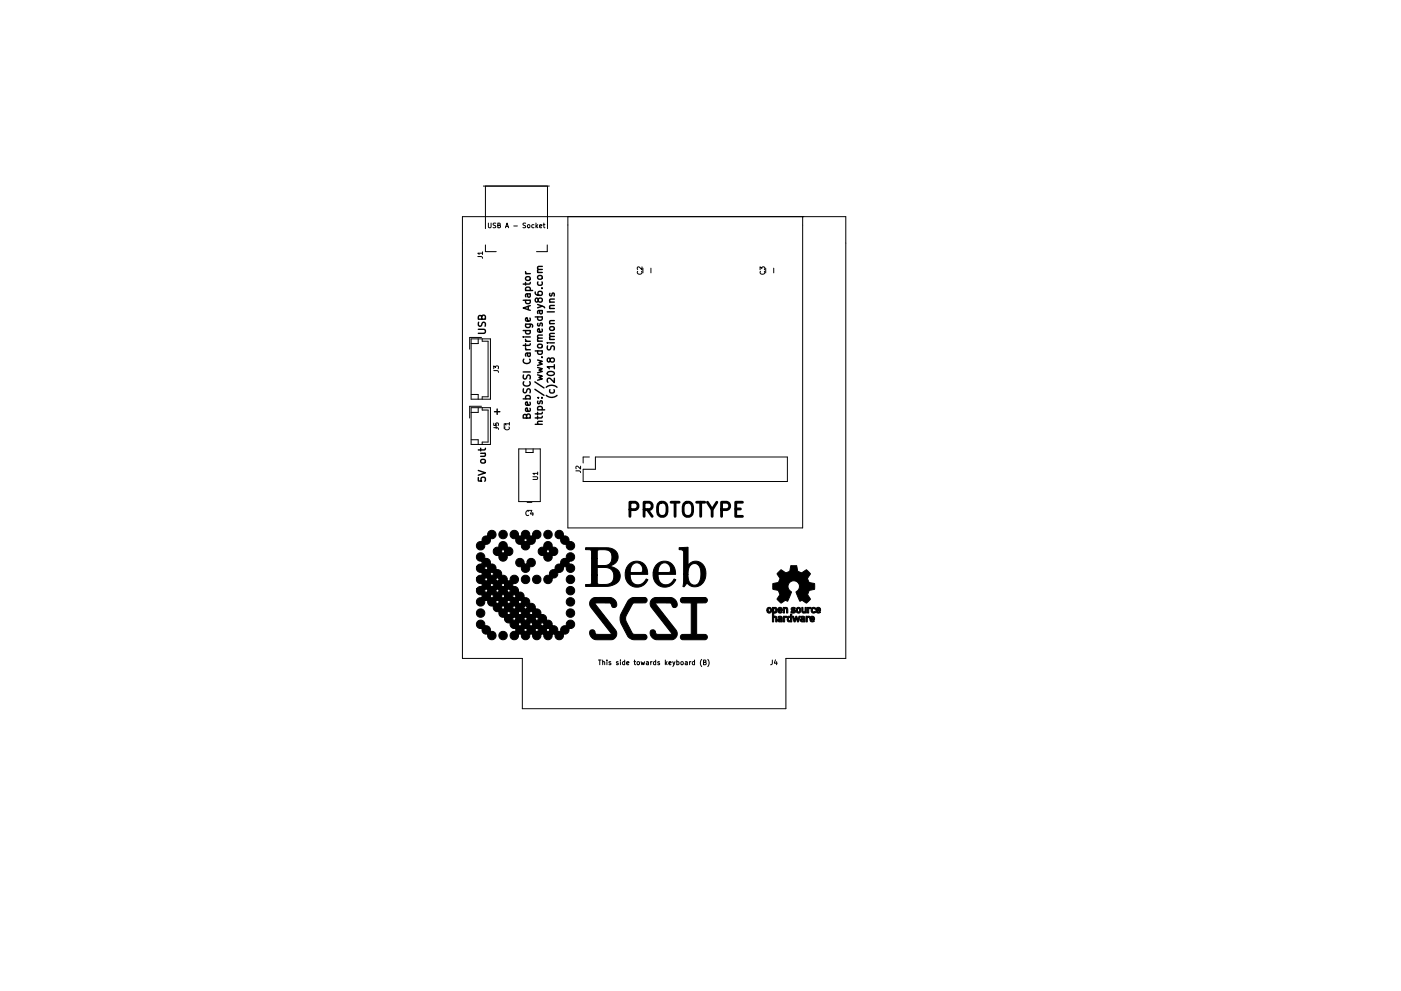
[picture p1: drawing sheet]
<svg xmlns="http://www.w3.org/2000/svg" width="297mm" height="210mm" viewBox="0 0 297 210" stroke-linecap="round" stroke-linejoin="round" font-family="sans-serif">
<g fill="none" stroke="#000" stroke-width=".3">
<path d="M111.4 57.6l.3 .5M111.4 59.9v.6M111.4 58.1h1M111.5 58.8l.6-.1 .3 .1v.4l-.3 .3h-.4l-.3-.3zM112.4 59.9l-.2 .4h-1.3M114 57.8h1M114.1 59.8l-.1 .4 .3 .3 .6-.1v-.6M114.1 58.5h.7l.2 .2-.1 .4-.2 .1h-.6l-.1-.2zM115 57.2h-.9l-.1 .4 .1 .2M115 56.5l-.9 .1-.1 .4 .2 .2M101.4 69.9h1.2l.3 .2v.3l-.3 .3h-1.2M101.5 68.4l-.1 .5 .3 .3 .4-.1 .2-.7h.5l.1 .2-.1 .6"/>
<path d="M102.1 67.2l.3-.3h.4l.1 .2v.6h-1.5l.2-.7 .2-.1 .3 .2v.6M110.9 71.5h.2M110.9 78.9h1.5M110.9 70.1h1.5M110.9 63.7h1.5M111 79.6l-.1 .5 .2 .2h.4l.3-.6 .3-.1 .3 .2v.6M111.1 76.2a.71 .71 0 0 0 .5 1 .71 .71 0 0 0 .8-.7l-.1-.3M111.4 73.8l.3 .4M111.4 72l.3 .4M111.4 68.8h1.2l.3 .3v.3M111.4 74.2h1M111.4 72.9v.6"/>
<path d="M111.4 72.4h1M111.4 71.5h1M111.4 61.6h1.5M111.5 70.1l-.1 .5 .3 .2 .7-.1v-.6M111.5 68.8l-.1 .4 .3 .3 .7-.2v-.5M111.5 63.7l-.1 .4 .3 .3 .7-.1v-.6M111.5 61.6l-.1-.4 .3-.3 .7 .2v.5M111.8 74.9l.1 .5 .2 .2 .3-.2v-.5M111.8 62.3l.1 .5 .2 .3 .3-.3v-.5M112 65v.7M112.4 67.5v.4l-.2 .2h-.7v-.6l.3-.1 .1 .7M112.4 74.9l-.9 .1v.6"/>
<path d="M112.4 72.9l-.2 .4h-1.3M112.4 64.8l-1.5 .5 1.5 .5M112.4 62.3l-.9 .1v.6M113.5 62v.4a1.01 1.01 0 0 0 1.5 0l-.2-.5-.5-.1-.2 .3v.4l.2 .2M113.5 74.5h1.5M113.5 67.2h1.5M114 79.5l1 .3-.7 .3 .7 .3-1 .3M114 78l1 .2-.7 .3 .7 .3-1 .3M114 76.4l1 .3-.7 .3 .7 .2-1 .3M114 64.6l1.3 .5 .2 .2M114 72.4h1M114.1 74.5l-.1 .4 .3 .3 .6-.2v-.5"/>
<path d="M114.1 68.6l-.1 .4 .2 .2 .2-.1 .1-.5h.4v.6M114.1 67.2l-.1 .5 .3 .3 .6-.2v-.6M114.1 73.1h.7l.2 .2-.1 .4-.2 .1-.6-.1-.1-.2zM114.1 63.5l.3-.3h.3l.3 .3-.2 .5-.4 .1-.2-.1-.2-.7-.5 .1v.4l.1 .2 .2 .1 .3-.3M114.3 65.9l.1 .5 .2 .2 .4-.2-.1-.5M114.8 75.8h.2M114.8 61.2h.2M114.9 69.8l.1 .4-.2 .3-.7-.1v-.6l.2-.1 .2 .8M115 71.7l-.9 .1-.1 .4 .1 .2M115 71.1l-.9 .1-.1 .3 .2 .2M115 65.9l-.9 .1v.5M115 65l-1 .3"/>
<path d="M116 72.7h.2M116 66.2h1.5M116.1 79a.89 .89 0 0 1 1.4 .3 .85 .85 0 0 1-1.5-.1zM116.1 73.4l-.1 .6 .2 .2h.4l.3-.7 .3-.1 .3 .3v.5M116.5 72.7h1M116.5 72h1M116.5 68.7h1M116.5 65.5h1M116.5 64.1h1M116.6 69.5l.6-.2 .3 .2v.3l-.3 .3h-.4l-.3-.3zM116.6 62.2l-.1 .4 .2 .2 .3-.1 .1-.5h.4v.6M116.7 76.2l.3-.2h.2l.3 .2v.5l-.5 .1-.3-.1-.2-.7-.4 .1-.1 .4 .2 .2 .2 .1 .3-.3"/>
<path d="M117.5 77.8h-1.5l.5 .4M117.5 71.4l-.9 .1-.1 .3 .2 .2M117.5 70.7l-.9 .1-.1 .4 .2 .2M117.5 68l-.9 .1-.1 .4 .2 .2M117.5 64.8l-.9 .1-.1 .3 .2 .3M117.5 63.5h-.9l-.1 .4 .2 .2M117.5 77.4v.8M101.4 99.8l1.5 .5-1.5 .5M101.9 96.2h1M101.9 95.1v.6M102 97.6l.6-.1 .2 .1 .1 .4-.3 .2h-.4l-.3-.2zM102.8 96.2l.1 .2-.1 .3-.9 .1"/>
<path d="M102.9 95.1l-.2 .4h-1.3M104.8 87.4h1.2M105.4 86.8v1.1M110.9 84.6h1.5M111 82.5l-.1 .6 .2 .2h.4l.3-.7 .3-.1 .3 .3v.5M111.1 81a.71 .71 0 0 0 .5 1 .71 .71 0 0 0 .8-.7l-.1-.3M111.5 84.6l-.1-.4 .3-.3 .7 .2v.5M111.6 88.2l.3-.4 .4 .1 .1 .2v.6h-1.5l.2-.7 .3-.1 .2 .2v.6M112.4 86.6v.5l-.2 .2-.7-.1v-.6h.3l.1 .7M112.4 85.3v.5l-.2 .2-.7-.1v-.6h.3l.1 .7M113.4 82.6l1.9 1.3M113.4 81l1.9 1.3"/>
<path d="M113.5 90h1.5M114 87.5v.5M114 88.3v.6M114 87h1.5M114.1 87l-.1-.5 .3-.3 .6 .2v.6M114.1 85.1l-.1 .4 .2 .2 .2-.1 .1-.5h.4v.6M114.1 84.4h.1M114.8 84.4h.2M115 89.4l-.9 .1-.1 .3 .1 .2M115 88.3l-.2 .4h-1.3M115 87.5l-.2 .3h-1.3M115.8 83.9a1.72 1.72 0 0 0 2.3 0"/>
<path d="M115.8 82.2a1.72 1.72 0 0 1 2.3 0M116.6 82.7l-.1 .4 .3 .3 .7-.2v-.5M117.5 80.2v1l-1-1-.5 .3 .2 .6M101.4 101.3v.7l.7 .1-.1-.2 .1-.5 .2-.2 .5 .1 .1 .2-.1 .6"/>
</g>
<g fill="none" stroke="#000" stroke-width=".21">
<path d="M102.5 39.5h14M102.9 39.5v9M116.1 39.5v9M98 46h81.3v93.7h-12.7v10.7h-55.9v-10.7h-12.7zM101.3 54.4l.9 .1 .1 .3M102.3 53.7h-1l.3 .3M102.3 53.4v.6M102.9 53.4h2.3M102.9 52v1.4M103.5 47.3v.8l.2 .2 .4-.2v-.8M105.1 47.4h-.5a.42 .42 0 0 0 .5 .5l-.1 .4h-.5M105.5 47.8h.5v-.4l-.5-.1v1h.4l.2-.3-.2-.2"/>
<path d="M107.2 48.3l.3-1 .3 1M107.3 48h.4M108.9 47.9h.8M111.5 47.4h-.6a.42 .42 0 0 0 .5 .5v.4h-.5M111.9 47.7h.3l.2 .1v.3l-.2 .2-.4-.2zM113.2 47.7h-.3l-.2 .1 .1 .5h.4M113.6 47.3v1M113.7 47.9l.3 .4M114 47.7l-.4 .3M114.4 48l.5-.1-.1-.2h-.3l-.1 .1 .1 .5h.3M115.2 47.7h.3M115.3 47.3v.9l.2 .1"/>
<path d="M116 52v1.4h-2.3M120.4 46v66h49.8v-66M135.2 57.6a.44 .44 0 0 0 .4 .6 .44 .44 0 0 0 .4-.6M136.1 56.6v.6l-.7-.6-.3 .2 .1 .4M136.3 56.9v1M138 56.9v1M161.1 57.2v-.6l.4 .3 .1-.2h.5v.5M161.2 57.6a.44 .44 0 0 0 .4 .6 .44 .44 0 0 0 .5-.6M162.3 56.9v1M164 56.9v1M99.9 71.9h4.1v12.8h-4.1zM101.4 71.9v1h-1.5"/>
<path d="M102.1 71.6h-2.5v2.5M102.2 71.9v.5h1.3v11.8h-1.3v.5M104.7 78.6l.8 .1 .2 .3M104.7 78.2v-.6l.4 .4 .1-.3h.4v.5M99.9 86.5h4.1v7.8h-4.1zM99.9 83.7h1.5v1M99.9 93.3h1.5v1M101.4 86.5v1h-1.5M102.1 86.2h-2.5v2.5M102.2 86.5v.5h1.3v6.8h-1.3v.5M104.7 90.7l.8 .1 .2 .3M104.7 89.8v.5h.5l-.1-.5h.5v.5"/>
<path d="M105.2 89.9v1M106.9 89.9v1M107.1 90.6a.44 .44 0 0 0 .4 .6 .44 .44 0 0 0 .4-.6M108 89.9h-1l.3 .3M108 89.6v.6M110 95.2h4.6v11.2h-4.6zM111.5 95.2v.8h1.5v-.8M122.1 99.9h.8l.2 .4M123.1 98.9v.6l-.7-.6-.3 .2 .1 .4M125 97h-1.4v1.2M126.2 97h40.7v5.2h-43.3v-2.6h2.6zM111.8 108.3h1"/>
<path d="M111.8 106.6h1M112.1 108.5a.44 .44 0 0 0-.6 .4 .44 .44 0 0 0 .6 .4M112.7 108.3l-.2 .8h.6M113 108.7v.7M113 101.1h.8l.2 .2-.2 .4h-.8M114 100.4h-1l.3 .3M114 100.1v.6M148.8 139.9a1.15 1.15 0 0 0 0 1.5M150.1 139.9a1.15 1.15 0 0 1 0 1.5M164.4 140l-.2 .7h.6M126.9 140h.5M127.2 140v1"/>
<path d="M127.8 140.5l.4-.1v.6M127.8 140v1M128.7 140v.1M128.7 140.4v.6M129.5 140.4l-.4 .1 .4 .2v.3h-.4M131.1 140.4l-.4 .1 .4 .2v.3h-.4M131.5 140v.1M131.5 140.4v.6M132.4 140.4h-.2l-.2 .2 .1 .4h.3M132.4 140v1M132.9 140.7l.5-.1-.1-.2h-.3l-.1 .1v.5h.4M134.4 140.4h.4"/>
<path d="M134.5 140v.9l.3 .1M135.1 140.5h.4v.5l-.4-.1zM135.9 140.4l.2 .6 .2-.4 .2 .4 .2-.6M137.1 140.4h.3l.1 .6M137.5 140.6l-.5 .2 .2 .2h.3M138 140.4v.6M138.3 140.4l-.3 .2M139 140.4h-.3l-.2 .2 .1 .4h.4M139 140v1M139.8 140.4l-.4 .1 .4 .2v.3h-.4M141.1 140v1M141.2 140.7l.2 .3"/>
<path d="M141.4 140.4l-.3 .3M141.8 140.7l.5-.1v-.2h-.3l-.2 .1 .1 .5h.4M142.6 140.4l.3 .6M143.1 140.4l-.5 1M143.5 140.4h.3l.2 .2-.1 .4h-.4M143.5 140v1M144.4 140.5h.4v.5l-.4-.1zM145.3 140.4h.4v.6M145.7 140.6l-.4 .2 .1 .2h.3M146.2 140.4v.6M146.5 140.4l-.3 .2M147.3 140.4h-.3l-.2 .2 .1 .4h.4"/>
<path d="M147.3 140v1M149.2 140.5h.4v-.4l-.4-.1v1h.3l.2-.3-.2-.2M163.8 140l-.1 .9-.3 .1M164.7 140.4v.6"/>
</g>
<g fill="none" stroke="#000" stroke-width=".6">
<path d="M133.6 108.1h1.1a.81 .81 0 0 0 .6-.8 .81 .81 0 0 0-.6-.7h-1.1v3M136.6 108.1h1.1a.81 .81 0 0 0 .6-.8 .81 .81 0 0 0-.6-.7h-1.1v3M137.3 108.1l1 1.5M139.6 107a1.01 1.01 0 0 1 1.1-.4 1.01 1.01 0 0 1 .7 1v1a1 1 0 0 1-1 1 1 1 0 0 1-1-1zM142.3 106.6h1.7M143.1 106.6v3M145 107a1.01 1.01 0 0 1 1.1-.4 1.01 1.01 0 0 1 .7 1v1a1 1 0 0 1-1 1 1 1 0 0 1-1-1zM147.7 106.6h1.7M148.6 106.6v3M150 106.6l1 1.5 1-1.5M151 108.1v1.5M153 108.1h1.1a.81 .81 0 0 0 .6-.8 .81 .81 0 0 0-.6-.7h-1.1v3"/>
<path d="M156 108h1M157.4 106.6h-1.4v3h1.4"/>
</g>
<g fill="#000" stroke="#000" stroke-width=".21">
<path d="M101.3 117.5l.5-.2a.89 .89 0 0 1 .9 1.2h.3a.9 .9 0 0 1 .9 1.2h.3a.9 .9 0 0 1 .9 1.2h.3a.9 .9 0 0 1 .9 1.2l.2-.1a.9 .9 0 0 1 1 1.3h.7v-.3a.9 .9 0 0 1 .9-1 .9 .9 0 0 1 .8 1.2 .9 .9 0 0 1-1.2 .6v.7l.2-.1a.9 .9 0 0 1 1 1.3l.2-.1a.9 .9 0 0 1 .9 1.3l.3-.1a.9 .9 0 0 1 .9 1.3l.3-.1a.9 .9 0 0 1 .9 1.3l.3-.1a.9 .9 0 0 1 .9 1.3l.3-.1a.9 .9 0 0 1 .9 1.2h.3a.9 .9 0 0 1 .9 1.2h.3a.9 .9 0 0 1 .9 1.2h.7v-.2a.9 .9 0 0 1 1.2-1v-.2a.9 .9 0 0 1 .9-1 .9 .9 0 0 1 .8 1.1 .9 .9 0 0 1-1.2 .6v.2a.9 .9 0 0 1-1.2 1l.1 .2a.9 .9 0 0 1-1.1 1 .9 .9 0 0 1-.7-1.2h-.7l.1 .2a.9 .9 0 0 1-1.1 1 .9 .9 0 0 1-.6-1.2h-.8l.1 .2a.9 .9 0 0 1-1 1 .9 .9 0 0 1-.7-1.2h-.8l.1 .2a.9 .9 0 0 1-1 1 .9 .9 0 0 1-.7-1.2h-.7v.2a.9 .9 0 0 1-.9 1 .9 .9 0 0 1-.8-1.1 .9 .9 0 0 1 1.2-.6v-.7h1.6l.1 .4a.19 .19 0 0 0 0 .3 .19 .19 0 0 0 .3 0h.4v-.7h1.6l.1 .4a.19 .19 0 0 0 0 .3 .19 .19 0 0 0 .3 0h.4v-.7h1.6l.1 .4a.19 .19 0 0 0 0 .3 .19 .19 0 0 0 .3 0h.4v-.7h-7.4a.9 .9 0 0 1-1-1.2h1.7v.4a.19 .19 0 0 0 0 .3 .19 .19 0 0 0 .3 0h.4v-.7h1.6l.1 .4a.19 .19 0 0 0 0 .3 .19 .19 0 0 0 .3 0h.4v-.7h1.6l.1 .4a.19 .19 0 0 0 0 .3 .19 .19 0 0 0 .3 0h.4v-.7l-7.4 .1a.9 .9 0 0 1-1-1.3h1.7v.4a.19 .19 0 0 0 .1 .3 .19 .19 0 0 0 .2 0h.4v-.7h1.6l.1 .4a.19 .19 0 0 0 0 .3 .19 .19 0 0 0 .3 0h.4v-.7h1.6l.1 .4a.19 .19 0 0 0 0 .3 .19 .19 0 0 0 .3 0h.4v-.7l-7.4 .1a.9 .9 0 0 1-1-1.3h1.7v.4a.19 .19 0 0 0 .1 .3 .19 .19 0 0 0 .3 0l.3 .1v-.8h1.7v.4a.19 .19 0 0 0 0 .3 .19 .19 0 0 0 .3 0l.4 .1v-.8h1.6l.1 .4a.19 .19 0 0 0 0 .3 .19 .19 0 0 0 .3 0l.4 .1v-.8l-7.4 .1a.9 .9 0 0 1-.9-1.3h1.6l.1 .5a.19 .19 0 0 0 0 .2 .19 .19 0 0 0 .3 0l.3 .1v-.8h1.7v.5a.19 .19 0 0 0 .1 .2 .19 .19 0 0 0 .2 0l.4 .1v-.8h1.6l.1 .5a.19 .19 0 0 0 0 .2 .19 .19 0 0 0 .3 0l.4 .1v-.8l-7.4 .1a.9 .9 0 0 1-.9-1.3h1.6l.1 .5a.19 .19 0 0 0 0 .3 .19 .19 0 0 0 .3-.1l.3 .1v-.8h1.7v.5a.19 .19 0 0 0 .1 .3 .19 .19 0 0 0 .3-.1l.3 .1v-.8h1.7v.5a.19 .19 0 0 0 0 .3 .19 .19 0 0 0 .3-.1l.4 .1v-.8h-7.9l.1 .2a.9 .9 0 0 1-.9 1.1 .9 .9 0 0 1-.9-1.1 .9 .9 0 0 1 1.3-.6v-.8h1.6l.1 .5a.19 .19 0 0 0 0 .3 .19 .19 0 0 0 .3-.1l.4 .1v-.8h1.6l.1 .5a.19 .19 0 0 0 0 .3 .19 .19 0 0 0 .3-.1l.3 .1v-.8h1.7v.5a.19 .19 0 0 0 .1 .3 .19 .19 0 0 0 .2-.1l.4 .1v-.8l-7.3 .1a.89 .89 0 0 1-1-1.3h1.6l.1 .5a.19 .19 0 0 0 0 .3 .19 .19 0 0 0 .3-.1l.4 .1v-.8h1.6l.1 .5a.19 .19 0 0 0 0 .3 .19 .19 0 0 0 .3-.1l.3 .1v-.8h1.7v.5a.19 .19 0 0 0 .1 .3 .19 .19 0 0 0 .3-.1l.3 .1v-.8h-7.1l.5-.4h.7v-.7h1.6l.1 .4a.19 .19 0 0 0 0 .3 .19 .19 0 0 0 .3-.1l.4 .1v-.7h1.6l.1 .4a.19 .19 0 0 0 0 .3 .19 .19 0 0 0 .3-.1l.3 .1v-.7h-5a.89 .89 0 0 1-.9-1.2h1.6l.1 .4a.19 .19 0 0 0 0 .3 .19 .19 0 0 0 .3-.1l.4 .1v-.7h1.6l.1 .4a.19 .19 0 0 0 0 .3 .19 .19 0 0 0 .3-.1l.3 .1v-.7h-4.7a.9 .9 0 0 1 1.2-.5v-.7h1.6l.1 .4a.19 .19 0 0 0 0 .3 .19 .19 0 0 0 .3-.1l.4 .1v-.7h-2.6a.89 .89 0 0 1-1-1.2h1.6l.1 .4a.19 .19 0 0 0 0 .3 .19 .19 0 0 0 .3 0h.4v-.7h-2.4l.5-.5h.7v-.7l-.3 .1a.89 .89 0 0 1-.9-.5 .89 .89 0 0 1 .2-1.1zM102.5 114l.4-.3 .6 .1-.1-.2a.9 .9 0 0 1 .9-1.1 .9 .9 0 0 1 .9 1.1 .9 .9 0 0 1-1.3 .6l.1 .2a.9 .9 0 0 1-1.3 1l.1 .2a.9 .9 0 0 1-.9 1.1 .9 .9 0 0 1-.9-1.1 .9 .9 0 0 1 1.3-.6l-.1-.6zM104.8 116.3l.5-.2 .5 .1v-.2a.9 .9 0 0 1 1-1.1 .9 .9 0 0 1 .7 1.3l.2-.1a.9 .9 0 0 1 1 1 .9 .9 0 0 1-1.2 .7v.2a.9 .9 0 0 1-1 1.1 .9 .9 0 0 1-.7-1.3l-.2 .1a.9 .9 0 0 1-.9-1.3h1.6l.1 .4a.19 .19 0 0 0 0 .3 .19 .19 0 0 0 .3 0l.3 .1v-.8h-2.3zM109.6 118.7l.6-.2a.89 .89 0 0 1 .8 1.2h.8l-.1-.2a.9 .9 0 0 1 .9-1 .9 .9 0 0 1 .9 1.1 .9 .9 0 0 1-1.3 .6l.1 .2a.9 .9 0 0 1-1 1 .9 .9 0 0 1-.7-1.2h-.2a.9 .9 0 0 1-1-.4 .9 .9 0 0 1 .2-1.1zM108.4 112.8l.6-.3a.89 .89 0 0 1 .9 1.3h.7l-.1-.3a.9 .9 0 0 1 1.1-1 .9 .9 0 0 1 .6 1.3h.8l-.1-.3a.9 .9 0 0 1 1-1 .9 .9 0 0 1 .8 1.1 .9 .9 0 0 1-1.3 .6l.1 .3a.9 .9 0 0 1-1.3 .9l.1 .3a.9 .9 0 0 1-1 1 .9 .9 0 0 1-.7-1.3l-.3 .1a.9 .9 0 0 1-.9-1.3h1.6l.1 .5a.19 .19 0 0 0 0 .3 .19 .19 0 0 0 .3-.1l.4 .1v-.8l-2.6 .1a.9 .9 0 0 1-1-.5 .9 .9 0 0 1 .2-1zM114.4 116.3l.4-.2 .6 .1-.1-.2a.9 .9 0 0 1 1-1.1 .9 .9 0 0 1 .7 1.3l.2-.1a.9 .9 0 0 1 1.1 1 .9 .9 0 0 1-1.3 .7l.1 .2a.9 .9 0 0 1-1 1.1 .9 .9 0 0 1-.7-1.3l-.2 .1a.9 .9 0 0 1-1-1.3h1.6l.1 .4a.19 .19 0 0 0 0 .3 .19 .19 0 0 0 .3 0l.4 .1v-.8h-2.4zM117.9 112.8l.6-.3a.89 .89 0 0 1 .9 1.3l.2-.1a.9 .9 0 0 1 1 1.3l.2-.1a.9 .9 0 0 1 1 .9 .9 .9 0 0 1-1.1 .9 .9 .9 0 0 1-.6-1.3l-.2 .1a.9 .9 0 0 1-1-1.3l-.2 .1a.9 .9 0 0 1-.9-.5 .9 .9 0 0 1 .1-1zM116.7 121.1l.5-.2h.5v-.2a.89 .89 0 0 1 1.2-1v-.2a.9 .9 0 0 1 1.2-1v-.2a.9 .9 0 0 1 .9-1 .9 .9 0 0 1 .8 1.1 .9 .9 0 0 1-1.2 .6v.7h.2a.9 .9 0 0 1 1 .9 .9 .9 0 0 1-1.1 .8 .9 .9 0 0 1-.6-1.2h-.7l.1 .2a.9 .9 0 0 1-1.3 1l.1 .2a.9 .9 0 0 1-1.3 1l.1 .2a.9 .9 0 0 1-1 1 .9 .9 0 0 1-.8-1.1 .9 .9 0 0 1 1.3-.6l-.1-.5zM124.2 116.2h4.8a1.94 1.94 0 0 1 2.1 1.9 1.94 1.94 0 0 1-1.9 2 2.24 2.24 0 0 1 2.3 2.5 2.95 2.95 0 0 1-2.7 1.8h-4.6v-.4h.9l.3-.2v-1.8h1.2v1a.68 .68 0 0 0 .6 1h1a1.8 1.8 0 0 0 1.9-1.8 1.8 1.8 0 0 0-1.9-1.8h-1.6v1.6h-1.2v-3.5h1.2v1.5h1.8a1.73 1.73 0 0 0 1.4-1.5 1.73 1.73 0 0 0-1-1.8l-1.8-.1a.69 .69 0 0 0-.4 1.1v.8h-1.2v-1.7l-.4-.2h-.8zM133.3 119.8a2.36 2.36 0 0 1 2.8-.5 2.36 2.36 0 0 1 1.2 2.6h-3.7v.2a1.75 1.75 0 0 0 1.4 1.9 1.75 1.75 0 0 0 2-1.2v.1a.26 .26 0 0 1 .4 .1 .26 .26 0 0 1-.2 .3 2.52 2.52 0 0 1-3.2 1.1 2.52 2.52 0 0 1-1.4-3h3.4a1.25 1.25 0 0 0 .1-1.3 1.25 1.25 0 0 0-1.2-.7 1.84 1.84 0 0 0-1.3 2h-1l.3-1zM139.3 119.8a2.36 2.36 0 0 1 2.7-.5 2.36 2.36 0 0 1 1.2 2.6h-3.7v.2a1.75 1.75 0 0 0 1.4 1.9 1.75 1.75 0 0 0 2-1.2l.1 .1a.26 .26 0 0 1 .3 .1 .26 .26 0 0 1-.2 .3 2.52 2.52 0 0 1-3.1 1.1 2.52 2.52 0 0 1-1.5-3h3.4a1.25 1.25 0 0 0 .1-1.3 1.25 1.25 0 0 0-1.2-.7 1.84 1.84 0 0 0-1.3 2h-1l.3-1zM144 116.2l1.9-.1v3.9a2.07 2.07 0 0 1 2.4-.8 2.07 2.07 0 0 1 1.4 2.2 2.46 2.46 0 0 1-.8 2.5 2.46 2.46 0 0 1-2.6 .4l-.7-.6-.2 .3a.41 .41 0 0 1-.5 .4v-2.5h1a1.84 1.84 0 0 0 1.2 2.2 1.3 1.3 0 0 0 1.4-1.4 2.78 2.78 0 0 0-.8-3 1.47 1.47 0 0 0-1.8 1.7v.5h-1v-4.8a.79 .79 0 0 0-.9-.5z"/>
<path d="M101.3 131.8l.5-.2a.89 .89 0 0 1 .9 1.2h.2a.9 .9 0 0 1 1 1.2h.2a.9 .9 0 0 1 1.1 .9 .9 .9 0 0 1-1.1 .8 .9 .9 0 0 1-.6-1.2h-.2a.9 .9 0 0 1-1-1.2h-.2a.9 .9 0 0 1-1-.4 .9 .9 0 0 1 .2-1.1zM125.4 127.1l.7-.3h2.7a1.51 1.51 0 0 1 1.8 1.9l-.3 .2a.85 .85 0 0 1-.8-.8l-2.5-.2a.61 .61 0 0 0-.8 .2l4.3 5.6a1.3 1.3 0 0 1-.7 2h-2.8a1.49 1.49 0 0 1-1.5-.4 1.49 1.49 0 0 1-.3-1.6h.7l.3 .7 .3 .2 3.1-.1-4.4-5.7a1.32 1.32 0 0 1 .2-1.7zM133.3 127.3l.5-.4 .6-.1h2.4l.4 .4-.1 .4-.3 .3-2.6 .1-1.4 2.6-.1 1.1 1.2 2.3a1.11 1.11 0 0 0 1.4 .6h1.4a.62 .62 0 0 1 .4 .9 .62 .62 0 0 1-.9 .2h-1.9l-.8-.3-.4-.4-1.2-2.4a2.57 2.57 0 0 1-.2-2.3zM138.2 127.1l.8-.3h2.7a1.51 1.51 0 0 1 1.7 1.9l-.3 .2a.85 .85 0 0 1-.8-.8l-2.5-.2a.61 .61 0 0 0-.8 .2l4.3 5.6a1.3 1.3 0 0 1-.7 2h-2.7a1.49 1.49 0 0 1-1.6-.4 1.49 1.49 0 0 1-.2-1.6h.6l.4 .7 .2 .2 3.1-.1-4.3-5.7a1.32 1.32 0 0 1 .1-1.7zM144.4 126.9l.3-.1h4.8a.59 .59 0 0 1 .5 .5 .59 .59 0 0 1-.5 .6h-1.8v6.7h1.9l.3 .3 .1 .5-.5 .3h-3.2h-1.6l-.4-.4v-.4l.4-.3h1.9v-6.7h-1.9a.59 .59 0 0 1-.3-1zM162.7 129a.56 .56 0 0 1 .8 .1 .56 .56 0 0 1-.1 .8 .56 .56 0 0 1-.8-.2v-.2h.2a.29 .29 0 0 0 .4 .3 .29 .29 0 0 0 .1-.5 .23 .23 0 0 0-.2-.2 .23 .23 0 0 0-.2 .2l-.1 .2h-.2zM163.8 128.9h.3a.49 .49 0 0 1 .6 .1 .49 .49 0 0 1 0 .6v.1a.41 .41 0 0 1-.2 .4 .41 .41 0 0 1-.5-.1v.8l.4-.1 .3 .3v1h-.2v-.9a.27 .27 0 0 0-.4 0 .27 .27 0 0 0-.1 .3v.5l-.2 .1v-2.5h.2l.1 .2a.29 .29 0 0 0 .4-.2 .29 .29 0 0 0-.4-.3l-.1 .3h-.2zM165 130.9a.55 .55 0 0 1 .7-.1 .55 .55 0 0 1 .2 .7v.5a.81 .81 0 0 1-1-.4l.3 .1a.23 .23 0 0 0 .3 0 .23 .23 0 0 0 .1-.3l-.7 .2 .1-.3 .6-.1a.36 .36 0 0 0-.6-.2zM165 129a.53 .53 0 0 1 .7 0 .53 .53 0 0 1 .2 .6h-.8l.2 .2 .4-.1 .1 .1a.54 .54 0 0 1-.7 .2 .54 .54 0 0 1-.2-.7h.7a.23 .23 0 0 0-.2-.2 .23 .23 0 0 0-.3 .2h-.2zM166.1 130.7l.8 .1-.5 .3v.9h-.3zM166.1 128.9h.3a.5 .5 0 0 1 .6 .1 .5 .5 0 0 1 0 .6v.5h-.2v-.6a.25 .25 0 0 0-.3-.4 .25 .25 0 0 0-.2 .4v.6h-.2zM167.1 130.8h.5v-.5h.3v1.7l-.3-.1a.45 .45 0 0 1-.5 0 .45 .45 0 0 1-.2-.5h.3a.25 .25 0 0 0 .3 .3 .25 .25 0 0 0 .1-.4 .23 .23 0 0 0-.3-.3 .23 .23 0 0 0-.1 .4h-.3z"/>
<path d="M167.8 129l.5-.1 .3 .1-.1 .2-.4-.1-.1 .2a.46 .46 0 0 1 .7 .5 .46 .46 0 0 1-.8 .2l-.3-.1 .2-.2a.28 .28 0 0 0 .3 .2 .28 .28 0 0 0 .3-.3 .44 .44 0 0 1-.5-.1 .44 .44 0 0 1-.1-.5zM168 130.7h.3l.2 .8 .2-.8h.2l.3 .8 .2-.8h.3l-.4 1.2-.2 .1-.3-.8-.2 .8h-.2zM165.3 121.2l.1-.1a.33 .33 0 0 1 .3-.2 .33 .33 0 0 1 .3 .2l.6 .5 .8-.4 .3-1.2h1.2l.2 1.2 .9 .4 .7-.6a.32 .32 0 0 1 .4-.1 .32 .32 0 0 1 .2 .3l.2 .2a.39 .39 0 0 1 .3 .4 .39 .39 0 0 1-.2 .4h-.1a.86 .86 0 0 0 .4 1.4l.4 .1a.39 .39 0 0 1 .4 .1 .39 .39 0 0 1 0 .5v.3a.34 .34 0 0 1 0 .4 .34 .34 0 0 1-.4 .1 .92 .92 0 0 0-1.1 1.1l.5 .7a.33 .33 0 0 1 .1 .4 .33 .33 0 0 1-.3 .2l-.3 .3a.3 .3 0 0 1-.3 .2 .3 .3 0 0 1-.3-.3h-.1a.68 .68 0 0 0-.9-.1l-.8-1.9a1.3 1.3 0 0 0 .6-1.5 1.3 1.3 0 0 0-1.3-1 1.27 1.27 0 0 0-1 1.1 1.27 1.27 0 0 0 .7 1.3l-.8 2a.77 .77 0 0 0-1.1 .2h-.1a.33 .33 0 0 1-.3 .2 .33 .33 0 0 1-.3-.4l-.2-.2a.42 .42 0 0 1-.3-.4 .42 .42 0 0 1 .3-.4 .95 .95 0 0 0 .1-1.1 .95 .95 0 0 0-1-.4 .33 .33 0 0 1-.3-.2 .33 .33 0 0 1 0-.4v-.3a.39 .39 0 0 1 .1-.4 .39 .39 0 0 1 .5-.1h.1a.86 .86 0 0 0 .7-1.3l-.3-.4a.32 .32 0 0 1-.1-.4 .32 .32 0 0 1 .3-.2zM168.9 129a.56 .56 0 0 1 .8 .1 .56 .56 0 0 1-.1 .8 .56 .56 0 0 1-.8-.1v-.3h.3v.1a.25 .25 0 0 0 .4 0 .25 .25 0 0 0 0-.3 .25 .25 0 0 0-.4 0v.2h-.3zM170 128.9h.2v.4a.33 .33 0 0 0 0 .4 .33 .33 0 0 0 .4 .1l.1-.9h.3v1.2l-.4-.1a.49 .49 0 0 1-.6-.1 .49 .49 0 0 1 0-.6zM169.8 130.9a.55 .55 0 0 1 .7-.1 .55 .55 0 0 1 .2 .7v.5l-.4-.1a.43 .43 0 0 1-.6-.3l.3 .1a.24 .24 0 0 0 .3 0 .24 .24 0 0 0 .1-.3l-.7 .2 .2-.3 .5-.1a.3 .3 0 0 0-.2-.3 .3 .3 0 0 0-.3 .1zM170.9 130.7l.3 .1a.25 .25 0 0 1 .2-.1 .25 .25 0 0 1 .2 .2l-.1 .1a.33 .33 0 0 0-.4 .2 .33 .33 0 0 0 .1 .4v.4h-.3zM171.2 128.9l.8 .1-.5 .2v.9h-.3zM171.8 130.9a.53 .53 0 0 1 .7-.1 .53 .53 0 0 1 .2 .6h-.7l.2 .3h.4a.5 .5 0 0 1-.7 .2 .5 .5 0 0 1-.2-.7h.7a.24 .24 0 0 0-.2-.2 .24 .24 0 0 0-.2 .2h-.3zM172.1 129a.41 .41 0 0 1 .4-.2 .41 .41 0 0 1 .4 .3l-.1 .1a.34 .34 0 0 0-.5 .1 .34 .34 0 0 0 .1 .5 .34 .34 0 0 0 .4-.1l.2 .2a.61 .61 0 0 1-.9 0 .61 .61 0 0 1 0-.9zM173.2 129a.52 .52 0 0 1 .6 0 .52 .52 0 0 1 .2 .6h-.7a.29 .29 0 0 0 .2 .3 .29 .29 0 0 0 .3-.2l.2 .2a.57 .57 0 0 1-.8 .1 .57 .57 0 0 1-.2-.7h.7a.23 .23 0 0 0-.2-.2 .23 .23 0 0 0-.2 .2h-.3z"/>
<circle cx="106.7" cy="113.4" r=".9"/>
<circle cx="116.2" cy="113.4" r=".9"/>
<circle cx="101.9" cy="130.1" r=".9"/>
<circle cx="106.7" cy="134.8" r=".9"/>
<circle cx="111.4" cy="122.9" r=".9"/>
<circle cx="113.8" cy="122.9" r=".9"/>
<circle cx="120.9" cy="130.1" r=".9"/>
<circle cx="120.9" cy="127.7" r=".9"/>
<circle cx="120.9" cy="125.3" r=".9"/>
<circle cx="120.9" cy="122.9" r=".9"/>
</g>
</svg>
